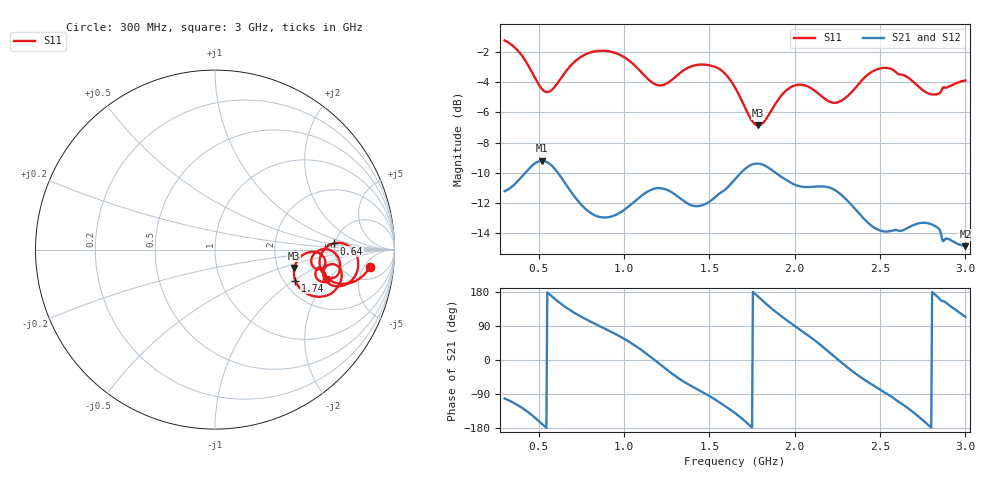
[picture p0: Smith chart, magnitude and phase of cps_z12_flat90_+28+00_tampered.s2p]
! cps_z12_flat90_+28+00_tampered
! simulated by sim/fixtures_fdtd.py (S12 = S21, S22 not computed)
# HZ S RI R 50
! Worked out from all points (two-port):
!   541 points, 300 MHz to 3 GHz, reference 50 ohm
!   highest |S21| = -9.20 dB at 520 MHz (marker M1); lowest = -14.9 dB at 3 GHz (marker M2)
!   |S21| within 3 dB of the highest: start of sweep to 756.8 MHz; 1.437 GHz to 2.339 GHz (902.2 MHz wide, 47.8 % of centre) (the widest 2 of 3)
!   lowest |S11| = -6.9 dB at 1.785 GHz (marker M3), VSWR 2.66, Z = 123 - j31.8 ohm
!   |S11| at or under -10 dB: nowhere
!   |S22| runs from - to - dB; largest |S21 - S12| = 0
!   S11 on the Smith chart (normalised r, x): 300 MHz: 9, -7; 640 MHz: 4.86, +0.60; 1.74 GHz: 2.30, -1.03; 3 GHz: 3.44, -1.90
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3e8  0.8631 -0.0967  -0.055 -0.2695  -0.055 -0.2695  0 0
4.25e8  0.714 -0.1912  -0.2189 -0.2313  -0.2189 -0.2313  0 0
5.2e8  0.589 -0.1075  -0.3403 -0.0659  -0.3403 -0.0659  0 0
6.4e8  0.6622 0.0345  -0.2464 0.1721  -0.2464 0.1721  0 0
7.5e8  0.7679 0.00104  -0.1004 0.2264  -0.1004 0.2264  0 0
8.85e8  0.7956 -0.1075  0.0264 0.2233  0.0264 0.2233  0 0
1.03e9  0.7173 -0.1991  0.1645 0.1823  0.1645 0.1823  0 0
1.2e9  0.6028 -0.1312  0.2788 -0.0374  0.2788 -0.0374  0 0
1.31e9  0.6597 -0.0814  0.1863 -0.1886  0.1863 -0.1886  0 0
1.45e9  0.7045 -0.1607  0.0323 -0.244  0.0323 -0.244  0 0
1.65e9  0.5484 -0.2592  -0.2307 -0.1937  -0.2307 -0.1937  0 0
1.74e9  0.4479 -0.1732  -0.3331 -0.0347  -0.3331 -0.0347  0 0
1.785e9  0.4422 -0.1021  -0.3311 0.0741  -0.3311 0.0741  0 0
1.925e9  0.5733 -0.0171  -0.1269 0.2781  -0.1269 0.2781  0 0
2.1e9  0.5917 -0.1071  0.1519 0.24  0.1519 0.24  0 0
2.26e9  0.5425 -0.0386  0.271 -0.0071  0.271 -0.0071  0 0
2.39e9  0.6374 -0.00105  0.1565 -0.1653  0.1565 -0.1653  0 0
2.55e9  0.6919 -0.1254  -0.00679 -0.2021  -0.00679 -0.2021  0 0
2.675e9  0.6224 -0.1785  -0.1371 -0.1584  -0.1371 -0.1584  0 0
2.78e9  0.5611 -0.1491  -0.2124 -0.0357  -0.2124 -0.0357  0 0
2.86e9  0.585 -0.1021  -0.1785 0.0778  -0.1785 0.0778  0 0
3e9  0.6187 -0.163  -0.0734 0.1651  -0.0734 0.1651  0 0
